VERSION 5.4 ;
NAMESCASESENSITIVE ON ;
BUSBITCHARS "[]" ;
DIVIDERCHAR "/" ;
UNITS
  DATABASE MICRONS 2000 ;
END UNITS
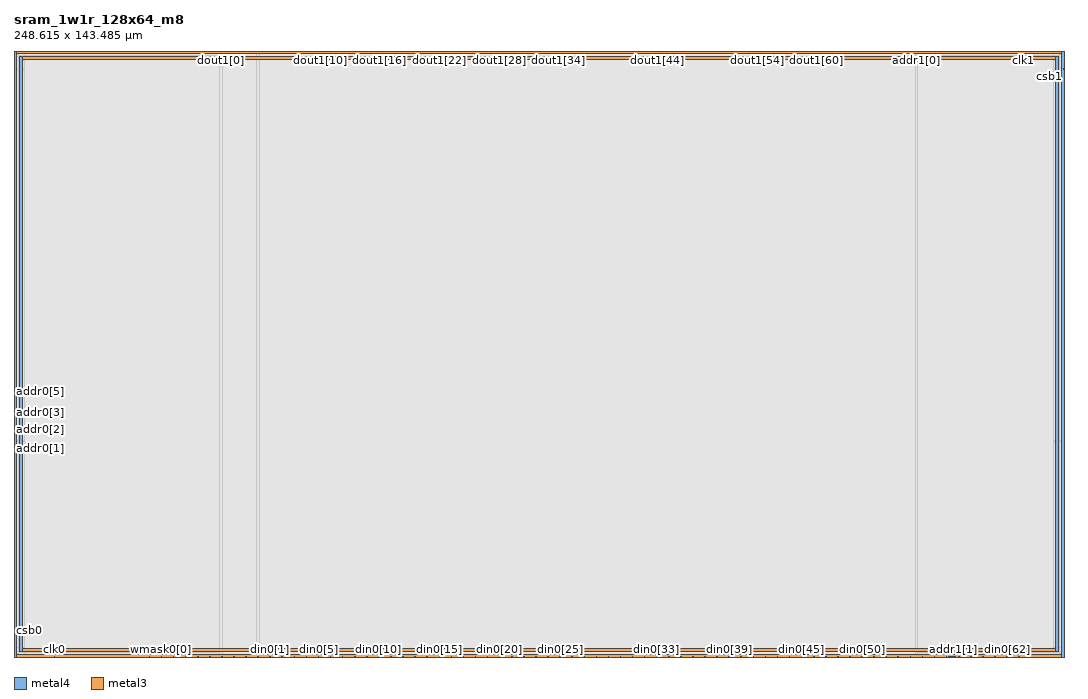
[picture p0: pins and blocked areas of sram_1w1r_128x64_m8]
MACRO sram_1w1r_128x64_m8
   CLASS BLOCK ;
   SIZE 248.615 BY 143.485 ;
   SYMMETRY X Y R90 ;
   PIN din0[0]
      DIRECTION INPUT ;
      PORT
         LAYER metal4 ;
         RECT  57.73 0.0 57.875 0.14 ;
      END
   END din0[0]
   PIN din0[1]
      DIRECTION INPUT ;
      PORT
         LAYER metal4 ;
         RECT  60.59 0.0 60.735 0.14 ;
      END
   END din0[1]
   PIN din0[2]
      DIRECTION INPUT ;
      PORT
         LAYER metal4 ;
         RECT  63.45 0.0 63.595 0.14 ;
      END
   END din0[2]
   PIN din0[3]
      DIRECTION INPUT ;
      PORT
         LAYER metal4 ;
         RECT  66.31 0.0 66.455 0.14 ;
      END
   END din0[3]
   PIN din0[4]
      DIRECTION INPUT ;
      PORT
         LAYER metal4 ;
         RECT  69.17 0.0 69.315 0.14 ;
      END
   END din0[4]
   PIN din0[5]
      DIRECTION INPUT ;
      PORT
         LAYER metal4 ;
         RECT  72.03 0.0 72.175 0.14 ;
      END
   END din0[5]
   PIN din0[6]
      DIRECTION INPUT ;
      PORT
         LAYER metal4 ;
         RECT  74.89 0.0 75.035 0.14 ;
      END
   END din0[6]
   PIN din0[7]
      DIRECTION INPUT ;
      PORT
         LAYER metal4 ;
         RECT  77.75 0.0 77.895 0.14 ;
      END
   END din0[7]
   PIN din0[8]
      DIRECTION INPUT ;
      PORT
         LAYER metal4 ;
         RECT  80.61 0.0 80.755 0.14 ;
      END
   END din0[8]
   PIN din0[9]
      DIRECTION INPUT ;
      PORT
         LAYER metal4 ;
         RECT  83.47 0.0 83.615 0.14 ;
      END
   END din0[9]
   PIN din0[10]
      DIRECTION INPUT ;
      PORT
         LAYER metal4 ;
         RECT  86.33 0.0 86.475 0.14 ;
      END
   END din0[10]
   PIN din0[11]
      DIRECTION INPUT ;
      PORT
         LAYER metal4 ;
         RECT  89.19 0.0 89.335 0.14 ;
      END
   END din0[11]
   PIN din0[12]
      DIRECTION INPUT ;
      PORT
         LAYER metal4 ;
         RECT  92.05 0.0 92.195 0.14 ;
      END
   END din0[12]
   PIN din0[13]
      DIRECTION INPUT ;
      PORT
         LAYER metal4 ;
         RECT  94.91 0.0 95.055 0.14 ;
      END
   END din0[13]
   PIN din0[14]
      DIRECTION INPUT ;
      PORT
         LAYER metal4 ;
         RECT  97.77 0.0 97.915 0.14 ;
      END
   END din0[14]
   PIN din0[15]
      DIRECTION INPUT ;
      PORT
         LAYER metal4 ;
         RECT  100.63 0.0 100.775 0.14 ;
      END
   END din0[15]
   PIN din0[16]
      DIRECTION INPUT ;
      PORT
         LAYER metal4 ;
         RECT  103.49 0.0 103.635 0.14 ;
      END
   END din0[16]
   PIN din0[17]
      DIRECTION INPUT ;
      PORT
         LAYER metal4 ;
         RECT  106.35 0.0 106.495 0.14 ;
      END
   END din0[17]
   PIN din0[18]
      DIRECTION INPUT ;
      PORT
         LAYER metal4 ;
         RECT  109.21 0.0 109.355 0.14 ;
      END
   END din0[18]
   PIN din0[19]
      DIRECTION INPUT ;
      PORT
         LAYER metal4 ;
         RECT  112.07 0.0 112.215 0.14 ;
      END
   END din0[19]
   PIN din0[20]
      DIRECTION INPUT ;
      PORT
         LAYER metal4 ;
         RECT  114.93 0.0 115.075 0.14 ;
      END
   END din0[20]
   PIN din0[21]
      DIRECTION INPUT ;
      PORT
         LAYER metal4 ;
         RECT  117.79 0.0 117.935 0.14 ;
      END
   END din0[21]
   PIN din0[22]
      DIRECTION INPUT ;
      PORT
         LAYER metal4 ;
         RECT  120.65 0.0 120.795 0.14 ;
      END
   END din0[22]
   PIN din0[23]
      DIRECTION INPUT ;
      PORT
         LAYER metal4 ;
         RECT  123.51 0.0 123.655 0.14 ;
      END
   END din0[23]
   PIN din0[24]
      DIRECTION INPUT ;
      PORT
         LAYER metal4 ;
         RECT  126.37 0.0 126.515 0.14 ;
      END
   END din0[24]
   PIN din0[25]
      DIRECTION INPUT ;
      PORT
         LAYER metal4 ;
         RECT  129.23 0.0 129.375 0.14 ;
      END
   END din0[25]
   PIN din0[26]
      DIRECTION INPUT ;
      PORT
         LAYER metal4 ;
         RECT  132.09 0.0 132.235 0.14 ;
      END
   END din0[26]
   PIN din0[27]
      DIRECTION INPUT ;
      PORT
         LAYER metal4 ;
         RECT  134.95 0.0 135.095 0.14 ;
      END
   END din0[27]
   PIN din0[28]
      DIRECTION INPUT ;
      PORT
         LAYER metal4 ;
         RECT  137.81 0.0 137.955 0.14 ;
      END
   END din0[28]
   PIN din0[29]
      DIRECTION INPUT ;
      PORT
         LAYER metal4 ;
         RECT  140.67 0.0 140.815 0.14 ;
      END
   END din0[29]
   PIN din0[30]
      DIRECTION INPUT ;
      PORT
         LAYER metal4 ;
         RECT  143.53 0.0 143.675 0.14 ;
      END
   END din0[30]
   PIN din0[31]
      DIRECTION INPUT ;
      PORT
         LAYER metal4 ;
         RECT  146.39 0.0 146.535 0.14 ;
      END
   END din0[31]
   PIN din0[32]
      DIRECTION INPUT ;
      PORT
         LAYER metal4 ;
         RECT  149.25 0.0 149.395 0.14 ;
      END
   END din0[32]
   PIN din0[33]
      DIRECTION INPUT ;
      PORT
         LAYER metal4 ;
         RECT  152.11 0.0 152.255 0.14 ;
      END
   END din0[33]
   PIN din0[34]
      DIRECTION INPUT ;
      PORT
         LAYER metal4 ;
         RECT  154.97 0.0 155.115 0.14 ;
      END
   END din0[34]
   PIN din0[35]
      DIRECTION INPUT ;
      PORT
         LAYER metal4 ;
         RECT  157.83 0.0 157.975 0.14 ;
      END
   END din0[35]
   PIN din0[36]
      DIRECTION INPUT ;
      PORT
         LAYER metal4 ;
         RECT  160.69 0.0 160.835 0.14 ;
      END
   END din0[36]
   PIN din0[37]
      DIRECTION INPUT ;
      PORT
         LAYER metal4 ;
         RECT  163.55 0.0 163.695 0.14 ;
      END
   END din0[37]
   PIN din0[38]
      DIRECTION INPUT ;
      PORT
         LAYER metal4 ;
         RECT  166.41 0.0 166.555 0.14 ;
      END
   END din0[38]
   PIN din0[39]
      DIRECTION INPUT ;
      PORT
         LAYER metal4 ;
         RECT  169.27 0.0 169.415 0.14 ;
      END
   END din0[39]
   PIN din0[40]
      DIRECTION INPUT ;
      PORT
         LAYER metal4 ;
         RECT  172.13 0.0 172.275 0.14 ;
      END
   END din0[40]
   PIN din0[41]
      DIRECTION INPUT ;
      PORT
         LAYER metal4 ;
         RECT  174.99 0.0 175.135 0.14 ;
      END
   END din0[41]
   PIN din0[42]
      DIRECTION INPUT ;
      PORT
         LAYER metal4 ;
         RECT  177.85 0.0 177.995 0.14 ;
      END
   END din0[42]
   PIN din0[43]
      DIRECTION INPUT ;
      PORT
         LAYER metal4 ;
         RECT  180.71 0.0 180.855 0.14 ;
      END
   END din0[43]
   PIN din0[44]
      DIRECTION INPUT ;
      PORT
         LAYER metal4 ;
         RECT  183.57 0.0 183.715 0.14 ;
      END
   END din0[44]
   PIN din0[45]
      DIRECTION INPUT ;
      PORT
         LAYER metal4 ;
         RECT  186.43 0.0 186.575 0.14 ;
      END
   END din0[45]
   PIN din0[46]
      DIRECTION INPUT ;
      PORT
         LAYER metal4 ;
         RECT  189.29 0.0 189.435 0.14 ;
      END
   END din0[46]
   PIN din0[47]
      DIRECTION INPUT ;
      PORT
         LAYER metal4 ;
         RECT  192.15 0.0 192.295 0.14 ;
      END
   END din0[47]
   PIN din0[48]
      DIRECTION INPUT ;
      PORT
         LAYER metal4 ;
         RECT  195.01 0.0 195.155 0.14 ;
      END
   END din0[48]
   PIN din0[49]
      DIRECTION INPUT ;
      PORT
         LAYER metal4 ;
         RECT  197.87 0.0 198.015 0.14 ;
      END
   END din0[49]
   PIN din0[50]
      DIRECTION INPUT ;
      PORT
         LAYER metal4 ;
         RECT  200.73 0.0 200.875 0.14 ;
      END
   END din0[50]
   PIN din0[51]
      DIRECTION INPUT ;
      PORT
         LAYER metal4 ;
         RECT  203.59 0.0 203.735 0.14 ;
      END
   END din0[51]
   PIN din0[52]
      DIRECTION INPUT ;
      PORT
         LAYER metal4 ;
         RECT  206.45 0.0 206.595 0.14 ;
      END
   END din0[52]
   PIN din0[53]
      DIRECTION INPUT ;
      PORT
         LAYER metal4 ;
         RECT  209.31 0.0 209.455 0.14 ;
      END
   END din0[53]
   PIN din0[54]
      DIRECTION INPUT ;
      PORT
         LAYER metal4 ;
         RECT  212.17 0.0 212.315 0.14 ;
      END
   END din0[54]
   PIN din0[55]
      DIRECTION INPUT ;
      PORT
         LAYER metal4 ;
         RECT  215.03 0.0 215.175 0.14 ;
      END
   END din0[55]
   PIN din0[56]
      DIRECTION INPUT ;
      PORT
         LAYER metal4 ;
         RECT  217.89 0.0 218.035 0.14 ;
      END
   END din0[56]
   PIN din0[57]
      DIRECTION INPUT ;
      PORT
         LAYER metal4 ;
         RECT  220.75 0.0 220.895 0.14 ;
      END
   END din0[57]
   PIN din0[58]
      DIRECTION INPUT ;
      PORT
         LAYER metal4 ;
         RECT  223.61 0.0 223.755 0.14 ;
      END
   END din0[58]
   PIN din0[59]
      DIRECTION INPUT ;
      PORT
         LAYER metal4 ;
         RECT  226.47 0.0 226.615 0.14 ;
      END
   END din0[59]
   PIN din0[60]
      DIRECTION INPUT ;
      PORT
         LAYER metal4 ;
         RECT  229.33 0.0 229.475 0.14 ;
      END
   END din0[60]
   PIN din0[61]
      DIRECTION INPUT ;
      PORT
         LAYER metal4 ;
         RECT  232.19 0.0 232.335 0.14 ;
      END
   END din0[61]
   PIN din0[62]
      DIRECTION INPUT ;
      PORT
         LAYER metal4 ;
         RECT  235.05 0.0 235.195 0.14 ;
      END
   END din0[62]
   PIN din0[63]
      DIRECTION INPUT ;
      PORT
         LAYER metal4 ;
         RECT  237.91 0.0 238.055 0.14 ;
      END
   END din0[63]
   PIN addr0[0]
      DIRECTION INPUT ;
      PORT
         LAYER metal4 ;
         RECT  31.99 0.0 32.135 0.14 ;
      END
   END addr0[0]
   PIN addr0[1]
      DIRECTION INPUT ;
      PORT
         LAYER metal3 ;
         RECT  0.0 51.065 0.14 51.21 ;
      END
   END addr0[1]
   PIN addr0[2]
      DIRECTION INPUT ;
      PORT
         LAYER metal3 ;
         RECT  0.0 53.795 0.14 53.94 ;
      END
   END addr0[2]
   PIN addr0[3]
      DIRECTION INPUT ;
      PORT
         LAYER metal3 ;
         RECT  0.0 56.005 0.14 56.15 ;
      END
   END addr0[3]
   PIN addr0[4]
      DIRECTION INPUT ;
      PORT
         LAYER metal3 ;
         RECT  0.0 58.735 0.14 58.88 ;
      END
   END addr0[4]
   PIN addr0[5]
      DIRECTION INPUT ;
      PORT
         LAYER metal3 ;
         RECT  0.0 60.945 0.14 61.09 ;
      END
   END addr0[5]
   PIN addr0[6]
      DIRECTION INPUT ;
      PORT
         LAYER metal3 ;
         RECT  0.0 63.675 0.14 63.82 ;
      END
   END addr0[6]
   PIN addr1[0]
      DIRECTION INPUT ;
      PORT
         LAYER metal4 ;
         RECT  213.62 143.34 213.765 143.485 ;
      END
   END addr1[0]
   PIN addr1[1]
      DIRECTION INPUT ;
      PORT
         LAYER metal4 ;
         RECT  222.485 0.0 222.625 0.14 ;
      END
   END addr1[1]
   PIN addr1[2]
      DIRECTION INPUT ;
      PORT
         LAYER metal4 ;
         RECT  221.345 0.0 221.485 0.14 ;
      END
   END addr1[2]
   PIN addr1[3]
      DIRECTION INPUT ;
      PORT
         LAYER metal4 ;
         RECT  221.63 0.0 221.77 0.14 ;
      END
   END addr1[3]
   PIN addr1[4]
      DIRECTION INPUT ;
      PORT
         LAYER metal4 ;
         RECT  222.77 0.0 222.91 0.14 ;
      END
   END addr1[4]
   PIN addr1[5]
      DIRECTION INPUT ;
      PORT
         LAYER metal4 ;
         RECT  221.915 0.0 222.055 0.14 ;
      END
   END addr1[5]
   PIN addr1[6]
      DIRECTION INPUT ;
      PORT
         LAYER metal4 ;
         RECT  222.2 0.0 222.34 0.14 ;
      END
   END addr1[6]
   PIN csb0
      DIRECTION INPUT ;
      PORT
         LAYER metal3 ;
         RECT  0.0 6.165 0.14 6.31 ;
      END
   END csb0
   PIN csb1
      DIRECTION INPUT ;
      PORT
         LAYER metal3 ;
         RECT  248.475 139.125 248.615 139.27 ;
      END
   END csb1
   PIN clk0
      DIRECTION INPUT ;
      PORT
         LAYER metal4 ;
         RECT  9.56 0.0 9.7 0.14 ;
      END
   END clk0
   PIN clk1
      DIRECTION INPUT ;
      PORT
         LAYER metal4 ;
         RECT  238.915 143.34 239.055 143.485 ;
      END
   END clk1
   PIN wmask0[0]
      DIRECTION INPUT ;
      PORT
         LAYER metal4 ;
         RECT  34.85 0.0 34.995 0.14 ;
      END
   END wmask0[0]
   PIN wmask0[1]
      DIRECTION INPUT ;
      PORT
         LAYER metal4 ;
         RECT  37.71 0.0 37.855 0.14 ;
      END
   END wmask0[1]
   PIN wmask0[2]
      DIRECTION INPUT ;
      PORT
         LAYER metal4 ;
         RECT  40.57 0.0 40.715 0.14 ;
      END
   END wmask0[2]
   PIN wmask0[3]
      DIRECTION INPUT ;
      PORT
         LAYER metal4 ;
         RECT  43.43 0.0 43.575 0.14 ;
      END
   END wmask0[3]
   PIN wmask0[4]
      DIRECTION INPUT ;
      PORT
         LAYER metal4 ;
         RECT  46.29 0.0 46.435 0.14 ;
      END
   END wmask0[4]
   PIN wmask0[5]
      DIRECTION INPUT ;
      PORT
         LAYER metal4 ;
         RECT  49.15 0.0 49.295 0.14 ;
      END
   END wmask0[5]
   PIN wmask0[6]
      DIRECTION INPUT ;
      PORT
         LAYER metal4 ;
         RECT  52.01 0.0 52.155 0.14 ;
      END
   END wmask0[6]
   PIN wmask0[7]
      DIRECTION INPUT ;
      PORT
         LAYER metal4 ;
         RECT  54.87 0.0 55.015 0.14 ;
      END
   END wmask0[7]
   PIN dout1[0]
      DIRECTION OUTPUT ;
      PORT
         LAYER metal4 ;
         RECT  48.965 143.34 49.11 143.485 ;
      END
   END dout1[0]
   PIN dout1[1]
      DIRECTION OUTPUT ;
      PORT
         LAYER metal4 ;
         RECT  51.315 143.34 51.46 143.485 ;
      END
   END dout1[1]
   PIN dout1[2]
      DIRECTION OUTPUT ;
      PORT
         LAYER metal4 ;
         RECT  53.665 143.34 53.81 143.485 ;
      END
   END dout1[2]
   PIN dout1[3]
      DIRECTION OUTPUT ;
      PORT
         LAYER metal4 ;
         RECT  56.015 143.34 56.16 143.485 ;
      END
   END dout1[3]
   PIN dout1[4]
      DIRECTION OUTPUT ;
      PORT
         LAYER metal4 ;
         RECT  58.365 143.34 58.51 143.485 ;
      END
   END dout1[4]
   PIN dout1[5]
      DIRECTION OUTPUT ;
      PORT
         LAYER metal4 ;
         RECT  60.715 143.34 60.86 143.485 ;
      END
   END dout1[5]
   PIN dout1[6]
      DIRECTION OUTPUT ;
      PORT
         LAYER metal4 ;
         RECT  63.065 143.34 63.21 143.485 ;
      END
   END dout1[6]
   PIN dout1[7]
      DIRECTION OUTPUT ;
      PORT
         LAYER metal4 ;
         RECT  65.415 143.34 65.56 143.485 ;
      END
   END dout1[7]
   PIN dout1[8]
      DIRECTION OUTPUT ;
      PORT
         LAYER metal4 ;
         RECT  67.765 143.34 67.91 143.485 ;
      END
   END dout1[8]
   PIN dout1[9]
      DIRECTION OUTPUT ;
      PORT
         LAYER metal4 ;
         RECT  70.115 143.34 70.26 143.485 ;
      END
   END dout1[9]
   PIN dout1[10]
      DIRECTION OUTPUT ;
      PORT
         LAYER metal4 ;
         RECT  72.465 143.34 72.61 143.485 ;
      END
   END dout1[10]
   PIN dout1[11]
      DIRECTION OUTPUT ;
      PORT
         LAYER metal4 ;
         RECT  74.815 143.34 74.96 143.485 ;
      END
   END dout1[11]
   PIN dout1[12]
      DIRECTION OUTPUT ;
      PORT
         LAYER metal4 ;
         RECT  77.165 143.34 77.31 143.485 ;
      END
   END dout1[12]
   PIN dout1[13]
      DIRECTION OUTPUT ;
      PORT
         LAYER metal4 ;
         RECT  79.515 143.34 79.66 143.485 ;
      END
   END dout1[13]
   PIN dout1[14]
      DIRECTION OUTPUT ;
      PORT
         LAYER metal4 ;
         RECT  81.865 143.34 82.01 143.485 ;
      END
   END dout1[14]
   PIN dout1[15]
      DIRECTION OUTPUT ;
      PORT
         LAYER metal4 ;
         RECT  84.215 143.34 84.36 143.485 ;
      END
   END dout1[15]
   PIN dout1[16]
      DIRECTION OUTPUT ;
      PORT
         LAYER metal4 ;
         RECT  86.565 143.34 86.71 143.485 ;
      END
   END dout1[16]
   PIN dout1[17]
      DIRECTION OUTPUT ;
      PORT
         LAYER metal4 ;
         RECT  88.915 143.34 89.06 143.485 ;
      END
   END dout1[17]
   PIN dout1[18]
      DIRECTION OUTPUT ;
      PORT
         LAYER metal4 ;
         RECT  91.265 143.34 91.41 143.485 ;
      END
   END dout1[18]
   PIN dout1[19]
      DIRECTION OUTPUT ;
      PORT
         LAYER metal4 ;
         RECT  93.615 143.34 93.76 143.485 ;
      END
   END dout1[19]
   PIN dout1[20]
      DIRECTION OUTPUT ;
      PORT
         LAYER metal4 ;
         RECT  95.965 143.34 96.11 143.485 ;
      END
   END dout1[20]
   PIN dout1[21]
      DIRECTION OUTPUT ;
      PORT
         LAYER metal4 ;
         RECT  98.315 143.34 98.46 143.485 ;
      END
   END dout1[21]
   PIN dout1[22]
      DIRECTION OUTPUT ;
      PORT
         LAYER metal4 ;
         RECT  100.665 143.34 100.81 143.485 ;
      END
   END dout1[22]
   PIN dout1[23]
      DIRECTION OUTPUT ;
      PORT
         LAYER metal4 ;
         RECT  103.015 143.34 103.16 143.485 ;
      END
   END dout1[23]
   PIN dout1[24]
      DIRECTION OUTPUT ;
      PORT
         LAYER metal4 ;
         RECT  105.365 143.34 105.51 143.485 ;
      END
   END dout1[24]
   PIN dout1[25]
      DIRECTION OUTPUT ;
      PORT
         LAYER metal4 ;
         RECT  107.715 143.34 107.86 143.485 ;
      END
   END dout1[25]
   PIN dout1[26]
      DIRECTION OUTPUT ;
      PORT
         LAYER metal4 ;
         RECT  110.065 143.34 110.21 143.485 ;
      END
   END dout1[26]
   PIN dout1[27]
      DIRECTION OUTPUT ;
      PORT
         LAYER metal4 ;
         RECT  112.415 143.34 112.56 143.485 ;
      END
   END dout1[27]
   PIN dout1[28]
      DIRECTION OUTPUT ;
      PORT
         LAYER metal4 ;
         RECT  114.765 143.34 114.91 143.485 ;
      END
   END dout1[28]
   PIN dout1[29]
      DIRECTION OUTPUT ;
      PORT
         LAYER metal4 ;
         RECT  117.115 143.34 117.26 143.485 ;
      END
   END dout1[29]
   PIN dout1[30]
      DIRECTION OUTPUT ;
      PORT
         LAYER metal4 ;
         RECT  119.465 143.34 119.61 143.485 ;
      END
   END dout1[30]
   PIN dout1[31]
      DIRECTION OUTPUT ;
      PORT
         LAYER metal4 ;
         RECT  121.815 143.34 121.96 143.485 ;
      END
   END dout1[31]
   PIN dout1[32]
      DIRECTION OUTPUT ;
      PORT
         LAYER metal4 ;
         RECT  124.165 143.34 124.31 143.485 ;
      END
   END dout1[32]
   PIN dout1[33]
      DIRECTION OUTPUT ;
      PORT
         LAYER metal4 ;
         RECT  126.515 143.34 126.66 143.485 ;
      END
   END dout1[33]
   PIN dout1[34]
      DIRECTION OUTPUT ;
      PORT
         LAYER metal4 ;
         RECT  128.865 143.34 129.01 143.485 ;
      END
   END dout1[34]
   PIN dout1[35]
      DIRECTION OUTPUT ;
      PORT
         LAYER metal4 ;
         RECT  131.215 143.34 131.36 143.485 ;
      END
   END dout1[35]
   PIN dout1[36]
      DIRECTION OUTPUT ;
      PORT
         LAYER metal4 ;
         RECT  133.565 143.34 133.71 143.485 ;
      END
   END dout1[36]
   PIN dout1[37]
      DIRECTION OUTPUT ;
      PORT
         LAYER metal4 ;
         RECT  135.915 143.34 136.06 143.485 ;
      END
   END dout1[37]
   PIN dout1[38]
      DIRECTION OUTPUT ;
      PORT
         LAYER metal4 ;
         RECT  138.265 143.34 138.41 143.485 ;
      END
   END dout1[38]
   PIN dout1[39]
      DIRECTION OUTPUT ;
      PORT
         LAYER metal4 ;
         RECT  140.615 143.34 140.76 143.485 ;
      END
   END dout1[39]
   PIN dout1[40]
      DIRECTION OUTPUT ;
      PORT
         LAYER metal4 ;
         RECT  142.965 143.34 143.11 143.485 ;
      END
   END dout1[40]
   PIN dout1[41]
      DIRECTION OUTPUT ;
      PORT
         LAYER metal4 ;
         RECT  145.315 143.34 145.46 143.485 ;
      END
   END dout1[41]
   PIN dout1[42]
      DIRECTION OUTPUT ;
      PORT
         LAYER metal4 ;
         RECT  147.665 143.34 147.81 143.485 ;
      END
   END dout1[42]
   PIN dout1[43]
      DIRECTION OUTPUT ;
      PORT
         LAYER metal4 ;
         RECT  150.015 143.34 150.16 143.485 ;
      END
   END dout1[43]
   PIN dout1[44]
      DIRECTION OUTPUT ;
      PORT
         LAYER metal4 ;
         RECT  152.365 143.34 152.51 143.485 ;
      END
   END dout1[44]
   PIN dout1[45]
      DIRECTION OUTPUT ;
      PORT
         LAYER metal4 ;
         RECT  154.715 143.34 154.86 143.485 ;
      END
   END dout1[45]
   PIN dout1[46]
      DIRECTION OUTPUT ;
      PORT
         LAYER metal4 ;
         RECT  157.065 143.34 157.21 143.485 ;
      END
   END dout1[46]
   PIN dout1[47]
      DIRECTION OUTPUT ;
      PORT
         LAYER metal4 ;
         RECT  159.415 143.34 159.56 143.485 ;
      END
   END dout1[47]
   PIN dout1[48]
      DIRECTION OUTPUT ;
      PORT
         LAYER metal4 ;
         RECT  161.765 143.34 161.91 143.485 ;
      END
   END dout1[48]
   PIN dout1[49]
      DIRECTION OUTPUT ;
      PORT
         LAYER metal4 ;
         RECT  164.115 143.34 164.26 143.485 ;
      END
   END dout1[49]
   PIN dout1[50]
      DIRECTION OUTPUT ;
      PORT
         LAYER metal4 ;
         RECT  166.465 143.34 166.61 143.485 ;
      END
   END dout1[50]
   PIN dout1[51]
      DIRECTION OUTPUT ;
      PORT
         LAYER metal4 ;
         RECT  168.815 143.34 168.96 143.485 ;
      END
   END dout1[51]
   PIN dout1[52]
      DIRECTION OUTPUT ;
      PORT
         LAYER metal4 ;
         RECT  171.165 143.34 171.31 143.485 ;
      END
   END dout1[52]
   PIN dout1[53]
      DIRECTION OUTPUT ;
      PORT
         LAYER metal4 ;
         RECT  173.515 143.34 173.66 143.485 ;
      END
   END dout1[53]
   PIN dout1[54]
      DIRECTION OUTPUT ;
      PORT
         LAYER metal4 ;
         RECT  175.865 143.34 176.01 143.485 ;
      END
   END dout1[54]
   PIN dout1[55]
      DIRECTION OUTPUT ;
      PORT
         LAYER metal4 ;
         RECT  178.215 143.34 178.36 143.485 ;
      END
   END dout1[55]
   PIN dout1[56]
      DIRECTION OUTPUT ;
      PORT
         LAYER metal4 ;
         RECT  180.565 143.34 180.71 143.485 ;
      END
   END dout1[56]
   PIN dout1[57]
      DIRECTION OUTPUT ;
      PORT
         LAYER metal4 ;
         RECT  182.915 143.34 183.06 143.485 ;
      END
   END dout1[57]
   PIN dout1[58]
      DIRECTION OUTPUT ;
      PORT
         LAYER metal4 ;
         RECT  185.265 143.34 185.41 143.485 ;
      END
   END dout1[58]
   PIN dout1[59]
      DIRECTION OUTPUT ;
      PORT
         LAYER metal4 ;
         RECT  187.615 143.34 187.76 143.485 ;
      END
   END dout1[59]
   PIN dout1[60]
      DIRECTION OUTPUT ;
      PORT
         LAYER metal4 ;
         RECT  189.965 143.34 190.11 143.485 ;
      END
   END dout1[60]
   PIN dout1[61]
      DIRECTION OUTPUT ;
      PORT
         LAYER metal4 ;
         RECT  192.315 143.34 192.46 143.485 ;
      END
   END dout1[61]
   PIN dout1[62]
      DIRECTION OUTPUT ;
      PORT
         LAYER metal4 ;
         RECT  194.665 143.34 194.81 143.485 ;
      END
   END dout1[62]
   PIN dout1[63]
      DIRECTION OUTPUT ;
      PORT
         LAYER metal4 ;
         RECT  197.015 143.34 197.16 143.485 ;
      END
   END dout1[63]
   PIN vdd
      DIRECTION INOUT ;
      USE POWER ; 
      SHAPE ABUTMENT ; 
      PORT
         LAYER metal4 ;
         RECT  0.0 0.0 0.7 143.485 ;
         LAYER metal3 ;
         RECT  0.0 142.78 248.615 143.485 ;
         LAYER metal3 ;
         RECT  0.0 0.0 248.615 0.7 ;
         LAYER metal4 ;
         RECT  247.915 0.0 248.615 143.485 ;
      END
   END vdd
   PIN gnd
      DIRECTION INOUT ;
      USE GROUND ; 
      SHAPE ABUTMENT ; 
      PORT
         LAYER metal4 ;
         RECT  246.515 1.4 247.215 142.085 ;
         LAYER metal3 ;
         RECT  1.4 141.38 247.215 142.085 ;
         LAYER metal3 ;
         RECT  1.4 1.4 247.215 2.1 ;
         LAYER metal4 ;
         RECT  1.4 1.4 2.1 142.085 ;
      END
   END gnd
   OBS
   LAYER  metal1 ;
      RECT  0.14 0.14 248.475 143.345 ;
   LAYER  metal2 ;
      RECT  0.14 0.14 248.475 143.345 ;
   LAYER  metal3 ;
      RECT  0.28 50.925 248.475 51.35 ;
      RECT  0.14 51.345 0.28 53.66 ;
      RECT  0.14 54.075 0.28 55.87 ;
      RECT  0.14 56.285 0.28 58.6 ;
      RECT  0.14 59.015 0.28 60.81 ;
      RECT  0.14 61.225 0.28 63.54 ;
      RECT  0.14 6.445 0.28 50.93 ;
      RECT  0.28 51.345 248.335 138.99 ;
      RECT  0.28 138.985 248.335 139.41 ;
      RECT  248.335 51.345 248.475 138.99 ;
      RECT  0.14 63.955 0.28 142.645 ;
      RECT  248.335 139.405 248.475 142.645 ;
      RECT  0.14 0.84 0.28 6.03 ;
      RECT  0.28 139.405 1.26 141.245 ;
      RECT  0.28 141.24 1.26 142.225 ;
      RECT  0.28 142.22 1.26 142.645 ;
      RECT  1.26 139.405 247.355 141.245 ;
      RECT  1.26 142.22 247.355 142.645 ;
      RECT  247.355 139.405 248.335 141.245 ;
      RECT  247.355 141.24 248.335 142.225 ;
      RECT  247.355 142.22 248.335 142.645 ;
      RECT  0.28 0.84 1.26 1.26 ;
      RECT  0.28 1.26 1.26 2.24 ;
      RECT  0.28 2.24 1.26 50.93 ;
      RECT  1.26 0.84 247.355 1.26 ;
      RECT  1.26 2.24 247.355 50.93 ;
      RECT  247.355 0.84 248.475 1.26 ;
      RECT  247.355 1.26 248.475 2.24 ;
      RECT  247.355 2.24 248.475 50.93 ;
   LAYER  metal4 ;
      RECT  58.15 0.14 60.315 0.42 ;
      RECT  61.01 0.14 63.175 0.42 ;
      RECT  63.87 0.14 66.035 0.42 ;
      RECT  66.73 0.14 68.895 0.42 ;
      RECT  69.59 0.14 71.755 0.42 ;
      RECT  72.45 0.14 74.615 0.42 ;
      RECT  75.31 0.14 77.475 0.42 ;
      RECT  78.17 0.14 80.335 0.42 ;
      RECT  81.03 0.14 83.195 0.42 ;
      RECT  83.89 0.14 86.055 0.42 ;
      RECT  86.75 0.14 88.915 0.42 ;
      RECT  89.61 0.14 91.775 0.42 ;
      RECT  92.47 0.14 94.635 0.42 ;
      RECT  95.33 0.14 97.495 0.42 ;
      RECT  98.19 0.14 100.355 0.42 ;
      RECT  101.05 0.14 103.215 0.42 ;
      RECT  103.91 0.14 106.075 0.42 ;
      RECT  106.77 0.14 108.935 0.42 ;
      RECT  109.63 0.14 111.795 0.42 ;
      RECT  112.49 0.14 114.655 0.42 ;
      RECT  115.35 0.14 117.515 0.42 ;
      RECT  118.21 0.14 120.375 0.42 ;
      RECT  121.07 0.14 123.235 0.42 ;
      RECT  123.93 0.14 126.095 0.42 ;
      RECT  126.79 0.14 128.955 0.42 ;
      RECT  129.65 0.14 131.815 0.42 ;
      RECT  132.51 0.14 134.675 0.42 ;
      RECT  135.37 0.14 137.535 0.42 ;
      RECT  138.23 0.14 140.395 0.42 ;
      RECT  141.09 0.14 143.255 0.42 ;
      RECT  143.95 0.14 146.115 0.42 ;
      RECT  146.81 0.14 148.975 0.42 ;
      RECT  149.67 0.14 151.835 0.42 ;
      RECT  152.53 0.14 154.695 0.42 ;
      RECT  155.39 0.14 157.555 0.42 ;
      RECT  158.25 0.14 160.415 0.42 ;
      RECT  161.11 0.14 163.275 0.42 ;
      RECT  163.97 0.14 166.135 0.42 ;
      RECT  166.83 0.14 168.995 0.42 ;
      RECT  169.69 0.14 171.855 0.42 ;
      RECT  172.55 0.14 174.715 0.42 ;
      RECT  175.41 0.14 177.575 0.42 ;
      RECT  178.27 0.14 180.435 0.42 ;
      RECT  181.13 0.14 183.295 0.42 ;
      RECT  183.99 0.14 186.155 0.42 ;
      RECT  186.85 0.14 189.015 0.42 ;
      RECT  189.71 0.14 191.875 0.42 ;
      RECT  192.57 0.14 194.735 0.42 ;
      RECT  195.43 0.14 197.595 0.42 ;
      RECT  198.29 0.14 200.455 0.42 ;
      RECT  201.15 0.14 203.315 0.42 ;
      RECT  204.01 0.14 206.175 0.42 ;
      RECT  206.87 0.14 209.035 0.42 ;
      RECT  209.73 0.14 211.895 0.42 ;
      RECT  212.59 0.14 214.755 0.42 ;
      RECT  215.45 0.14 217.615 0.42 ;
      RECT  218.31 0.14 220.475 0.42 ;
      RECT  224.03 0.14 226.195 0.42 ;
      RECT  226.89 0.14 229.055 0.42 ;
      RECT  229.75 0.14 231.915 0.42 ;
      RECT  232.61 0.14 234.775 0.42 ;
      RECT  235.47 0.14 237.635 0.42 ;
      RECT  58.15 0.42 213.345 143.065 ;
      RECT  213.34 0.42 214.045 143.065 ;
      RECT  223.19 0.14 223.335 0.42 ;
      RECT  9.98 0.14 31.715 0.42 ;
      RECT  214.04 143.06 238.635 143.345 ;
      RECT  32.41 0.14 34.575 0.42 ;
      RECT  35.27 0.14 37.435 0.42 ;
      RECT  38.13 0.14 40.295 0.42 ;
      RECT  40.99 0.14 43.155 0.42 ;
      RECT  43.85 0.14 46.015 0.42 ;
      RECT  46.71 0.14 48.875 0.42 ;
      RECT  49.57 0.14 51.735 0.42 ;
      RECT  52.43 0.14 54.595 0.42 ;
      RECT  55.29 0.14 57.455 0.42 ;
      RECT  48.685 0.42 49.39 143.065 ;
      RECT  49.385 0.42 57.455 143.065 ;
      RECT  49.385 143.06 51.04 143.345 ;
      RECT  51.735 143.06 53.39 143.345 ;
      RECT  54.085 143.06 55.74 143.345 ;
      RECT  56.435 143.06 57.455 143.345 ;
      RECT  57.45 0.42 58.09 143.065 ;
      RECT  57.45 143.06 58.09 143.345 ;
      RECT  58.085 0.42 58.155 143.065 ;
      RECT  58.785 143.06 60.44 143.345 ;
      RECT  61.135 143.06 62.79 143.345 ;
      RECT  63.485 143.06 65.14 143.345 ;
      RECT  65.835 143.06 67.49 143.345 ;
      RECT  68.185 143.06 69.84 143.345 ;
      RECT  70.535 143.06 72.19 143.345 ;
      RECT  72.885 143.06 74.54 143.345 ;
      RECT  75.235 143.06 76.89 143.345 ;
      RECT  77.585 143.06 79.24 143.345 ;
      RECT  79.935 143.06 81.59 143.345 ;
      RECT  82.285 143.06 83.94 143.345 ;
      RECT  84.635 143.06 86.29 143.345 ;
      RECT  86.985 143.06 88.64 143.345 ;
      RECT  89.335 143.06 90.99 143.345 ;
      RECT  91.685 143.06 93.34 143.345 ;
      RECT  94.035 143.06 95.69 143.345 ;
      RECT  96.385 143.06 98.04 143.345 ;
      RECT  98.735 143.06 100.39 143.345 ;
      RECT  101.085 143.06 102.74 143.345 ;
      RECT  103.435 143.06 105.09 143.345 ;
      RECT  105.785 143.06 107.44 143.345 ;
      RECT  108.135 143.06 109.79 143.345 ;
      RECT  110.485 143.06 112.14 143.345 ;
      RECT  112.835 143.06 114.49 143.345 ;
      RECT  115.185 143.06 116.84 143.345 ;
      RECT  117.535 143.06 119.19 143.345 ;
      RECT  119.885 143.06 121.54 143.345 ;
      RECT  122.235 143.06 123.89 143.345 ;
      RECT  124.585 143.06 126.24 143.345 ;
      RECT  126.935 143.06 128.59 143.345 ;
      RECT  129.285 143.06 130.94 143.345 ;
      RECT  131.635 143.06 133.29 143.345 ;
      RECT  133.985 143.06 135.64 143.345 ;
      RECT  136.335 143.06 137.99 143.345 ;
      RECT  138.685 143.06 140.34 143.345 ;
      RECT  141.035 143.06 142.69 143.345 ;
      RECT  143.385 143.06 145.04 143.345 ;
      RECT  145.735 143.06 147.39 143.345 ;
      RECT  148.085 143.06 149.74 143.345 ;
      RECT  150.435 143.06 152.09 143.345 ;
      RECT  152.785 143.06 154.44 143.345 ;
      RECT  155.135 143.06 156.79 143.345 ;
      RECT  157.485 143.06 159.14 143.345 ;
      RECT  159.835 143.06 161.49 143.345 ;
      RECT  162.185 143.06 163.84 143.345 ;
      RECT  164.535 143.06 166.19 143.345 ;
      RECT  166.885 143.06 168.54 143.345 ;
      RECT  169.235 143.06 170.89 143.345 ;
      RECT  171.585 143.06 173.24 143.345 ;
      RECT  173.935 143.06 175.59 143.345 ;
      RECT  176.285 143.06 177.94 143.345 ;
      RECT  178.635 143.06 180.29 143.345 ;
      RECT  180.985 143.06 182.64 143.345 ;
      RECT  183.335 143.06 184.99 143.345 ;
      RECT  185.685 143.06 187.34 143.345 ;
      RECT  188.035 143.06 189.69 143.345 ;
      RECT  190.385 143.06 192.04 143.345 ;
      RECT  192.735 143.06 194.39 143.345 ;
      RECT  195.085 143.06 196.74 143.345 ;
      RECT  197.435 143.06 213.345 143.345 ;
      RECT  0.98 0.14 9.28 0.42 ;
      RECT  0.98 143.06 48.69 143.345 ;
      RECT  238.33 0.14 247.635 0.42 ;
      RECT  239.335 143.06 247.635 143.345 ;
      RECT  214.04 0.42 246.235 1.12 ;
      RECT  214.04 1.12 246.235 142.365 ;
      RECT  214.04 142.36 246.235 143.065 ;
      RECT  246.235 0.42 247.495 1.12 ;
      RECT  246.235 142.36 247.495 143.065 ;
      RECT  247.495 0.42 247.635 1.12 ;
      RECT  247.495 1.12 247.635 142.365 ;
      RECT  247.495 142.36 247.635 143.065 ;
      RECT  0.98 0.42 1.12 1.12 ;
      RECT  0.98 1.12 1.12 142.365 ;
      RECT  0.98 142.36 1.12 143.065 ;
      RECT  1.12 0.42 2.38 1.12 ;
      RECT  1.12 142.36 2.38 143.065 ;
      RECT  2.38 0.42 48.69 1.12 ;
      RECT  2.38 1.12 48.69 142.365 ;
      RECT  2.38 142.36 48.69 143.065 ;
   END
END    sram_1w1r_128x64_m8
END    LIBRARY
